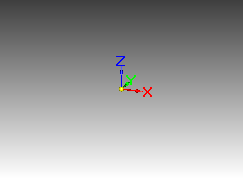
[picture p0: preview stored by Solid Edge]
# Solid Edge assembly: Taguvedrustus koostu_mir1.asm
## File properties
Author: Türk
Template: Iso Assembly.asm
Last saved by: Türk
Revision: 2
Application: Solid Edge
Username: Türk
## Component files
Hoidja.tagu.par
